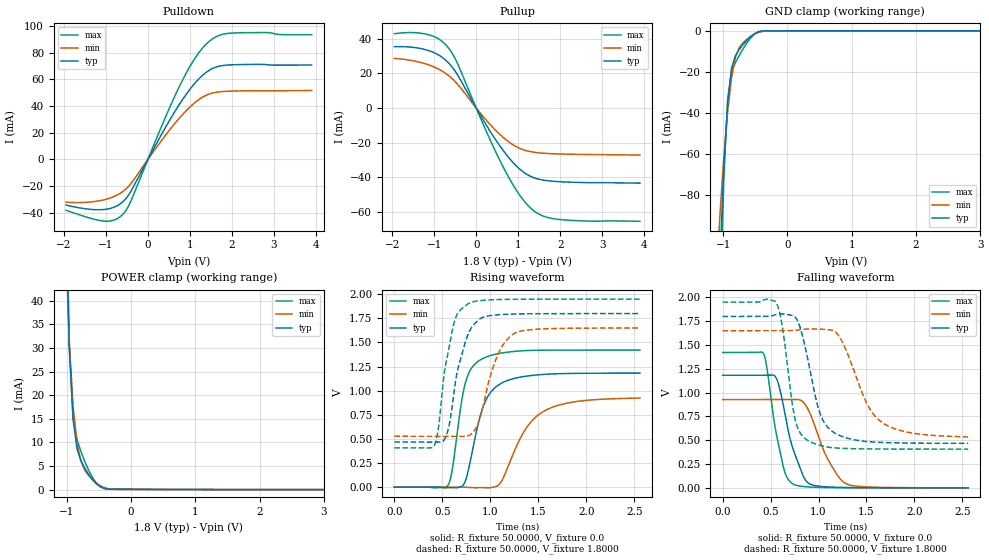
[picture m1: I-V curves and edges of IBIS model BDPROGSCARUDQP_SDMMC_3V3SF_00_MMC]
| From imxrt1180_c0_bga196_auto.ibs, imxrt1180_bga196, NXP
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[Model]  BDPROGSCARUDQP_SDMMC_3V3SF_00_MMC
|   Model BDPROGSCARUDQP_SDMMC_3V3SF_00_MMC
| This model was characterised for following simulation conditions:
| External (pad) voltage:
|   - Typ: 1.8V,   - Min: 1.65V,   - Max: 1.95V
| Library cells for typ/min/max conditions are connected as defined below:
|  IO - External Pad
|  A - Core Input
|  EN - Output Buffer Enable
|  ASRCN3V3[0] - gnde REFH3V3 gnde
|  ASRCN3V3[1] - REFH3V3 gnde gnde
|  ASRCN3V3[2] - gnde
|  ASRCN3V3[3] - gnde REFH3V3 gnde
|  ASRCP3V3[0] - vdde3v3 vdde3v3 REFL3V3
|  ASRCP3V3[1] - vdde3v3 REFL3V3 vdde3v3
|  ASRCP3V3[2] - REFL3V3 vdde3v3 vdde3v3
|  ASRCP3V3[3] - vdde3v3 REFL3V3 vdde3v3
|  IOGC - NC
|  PDRV - gnd
|  PSW - gnd
|  REFH3V3 - REFH3V3
|  REFL3V3 - REFL3V3
|  ZI - NC
|  gnd - gnd
|  gnde - gnde
|  vdd - vdd
|  vdde3v3 - vdde3v3
| All other pins connected to ground
Model_type I/O
Polarity   Non-Inverting
Enable   Active-Low
Vinl =   0.5775V
Vinh =   1.2675V
Vmeas =  0.9000V
Cref =   30.0000pF
Rref =   1.0000M
Vref =   1.8000V
C_comp   2.2202pF   2.2075pF   2.2420pF
|C_comp_pullup   1.1647pF   1.1330pF   1.1987pF
|C_comp_pulldown   0.7687pF   0.7963pF   0.7473pF
[Model Spec]
| variable   typ   min   max
Vinh   1.1700V   1.0725V   1.2675V
Vinl   0.6300V   0.5775V   0.6825V
[Temperature Range]   25.0000   0.1250k   -40.0000
[Voltage Range]   1.8000V   1.6500V   1.9500V
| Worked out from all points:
|   slope of the pulldown table from 0 to 0.27 V, typ, clamps not added: 17.2 ohm
|   slope of the pullup table from 0 to 0.27 V, typ, clamps not added: 24.6 ohm
|   GND clamp passes 1 mA (typ) near -0.49 V on its own axis
|   POWER clamp passes 1 mA (typ) near -0.52 V on its own axis
|   rising waveform, R_fixture 50.0000, V_fixture 0.0: 20-80 % time 193ps typ, 314ps min, 138ps max; typ from 0 V to 1.18 V
|   rising waveform, R_fixture 50.0000, V_fixture 1.8000: 20-80 % time 161ps typ, 200ps min, 135ps max; typ from 0.468 V to 1.8 V
|   falling waveform, R_fixture 50.0000, V_fixture 0.0: 20-80 % time 180ps typ, 236ps min, 140ps max; typ from 1.18 V to 0 V
|   falling waveform, R_fixture 50.0000, V_fixture 1.8000: 20-80 % time 186ps typ, 290ps min, 126ps max; typ from 1.8 V to 0.468 V
[Pulldown]
|Voltage   I(typ)   I(min)   I(max)
-1.95V    -34.28mA   -32.14mA   -38.27mA
-990mV    -37.37mA   -29.86mA   -46.43mA
-750mV    -35.06mA   -27.04mA   -44.73mA
-570mV    -31.01mA   -23.44mA   -40.26mA
-390mV    -23.02mA   -17.53mA   -30.03mA
390mV     22.39mA    16.91mA    29.6mA
810mV     44.08mA    33.05mA    58.46mA
1.17V     58.87mA    43.79mA    78.04mA
1.53V     67.94mA    49.57mA    90.07mA
1.77V     70.2mA     50.73mA    93.56mA
2.07V     70.86mA    51.18mA    94.66mA
3.9V      70.64mA    51.55mA    93.34mA
[Pullup]
|Voltage   I(typ)   I(min)   I(max)
-1.95V    35.27mA    28.54mA    42.76mA
-1.14V    33.09mA    24.9mA     42.2mA
-900mV    30.57mA    22.44mA    39.86mA
-660mV    25.99mA    18.7mA     34.59mA
-420mV    18.1mA     13.04mA    24.29mA
240mV     -9.816mA   -6.997mA   -13.39mA
660mV     -25.01mA   -17.28mA   -34.76mA
1.02V     -34.83mA   -23.05mA   -49.63mA
1.38V     -40.19mA   -25.49mA   -59.33mA
1.68V     -41.81mA   -26.16mA   -62.9mA
2.04V     -42.5mA    -26.5mA    -64.33mA
3.9V      -43.26mA   -27.06mA   -65.23mA
[GND_clamp]
|Voltage   I(typ)   I(min)   I(max)
-1.95V    -1.789A    -1.004A    -3.051A
-1.11V    -176.3mA   -125mA     -253.2mA
-1.05V    -112.3mA   -89.65mA   -141mA
-990mV    -66.82mA   -61.56mA   -72.04mA
-930mV    -35.58mA   -39.41mA   -33.25mA
-870mV    -18.33mA   -22.88mA   -19.96mA
-810mV    -12.12mA   -12.84mA   -15.54mA
-750mV    -9.12mA    -8.155mA   -12.04mA
-630mV    -4.535mA   -4.075mA   -5.883mA
-510mV    -1.335mA   -1.581mA   -1.518mA
-270mV    -20.22uA   -28.48uA   -26.21uA
3.9V      0A         0A         0A
[POWER_clamp]
|Voltage   I(typ)   I(min)   I(max)
-1.95V    1.733A     958.6mA    2.996A
-1.02V    63.28mA    53.98mA    74.85mA
-960mV    30.45mA    31.34mA    30.44mA
-900mV    14.89mA    17.65mA    15.05mA
-840mV    8.668mA    9.912mA    10.62mA
-780mV    6.192mA    6.041mA    8.133mA
-720mV    4.573mA    4.149mA    5.993mA
-600mV    2.107mA    2.103mA    2.589mA
-480mV    625.6uA    842.7uA    634.5uA
-360mV    113.4uA    223.3uA    106.8uA
-180mV    54.75uA    42.77uA    75.45uA
3.9V      0A         0A         0A
[Ramp]
| variable   typ   min   max
dV/dt_r  0.7089/0.1931n   0.5536/0.3137n   0.8526/0.1382n
dV/dt_f  0.7989/0.1861n   0.6687/0.2896n   0.9253/0.1263n
R_load = 50.0000
[Rising Waveform]
R_fixture= 50.0000
V_fixture= 0.0
V_fixture_min= 0.0
V_fixture_max= 0.0
|time   V(typ)   V(min)   V(max)
0s        129.7uV    120.6uV    150.1uV
558.8ps   -7.311mV   123uV      17.56mV
600.7ps   -5.725mV   190.1uV    163mV
690.8ps   3.688mV    66.72uV    822.9mV
738.3ps   57.62mV    -1.964mV   1.074V
908.6ps   783.2mV    -5.56mV    1.326V
1.102ns   1.069V     37.87mV    1.388V
1.369ns   1.15V      603.9mV    1.415V
1.577ns   1.17V      797mV      1.42V
2.56ns    1.182V     922.8mV    1.421V
[Rising Waveform]
R_fixture= 50.0000
V_fixture= 1.8000
V_fixture_min= 1.6500
V_fixture_max= 1.9500
|time   V(typ)   V(min)   V(max)
0s        467.5mV    526.6mV    407.1mV
418.4ps   467.6mV    526.7mV    435.2mV
461.2ps   466.1mV    526.7mV    620.9mV
532.5ps   512.2mV    526.7mV    1.256V
613.1ps   918.5mV    526.7mV    1.667V
778.4ps   1.609V     535.3mV    1.907V
885.2ps   1.74V      688.4mV    1.933V
1.081ns   1.787V     1.377V     1.945V
1.243ns   1.794V     1.589V     1.948V
2.56ns    1.799V     1.649V     1.949V
[Falling Waveform]
R_fixture= 50.0000
V_fixture= 0.0
V_fixture_min= 0.0
V_fixture_max= 0.0
|time   V(typ)   V(min)   V(max)
0s        1.182V     926.4mV    1.421V
426.1ps   1.181V     926.5mV    1.41V
461ps     1.181V     926.6mV    1.267V
567.9ps   1.134V     926.5mV    527.9mV
649.7ps   782.1mV    926.4mV    161.1mV
729.3ps   424.2mV    927.5mV    43.73mV
894.3ps   50.19mV    818.3mV    9.87mV
1.092ns   9.927mV    310.5mV    3.186mV
1.277ns   3.856mV    49.37mV    1.308mV
2.56ns    148.6uV    453uV      151.8uV
[Falling Waveform]
R_fixture= 50.0000
V_fixture= 1.8000
V_fixture_min= 1.6500
V_fixture_max= 1.9500
|time   V(typ)   V(min)   V(max)
0s        1.799V     1.649V     1.949V
562.2ps   1.821V     1.649V     1.938V
623.9ps   1.826V     1.649V     1.687V
759.3ps   1.79V      1.652V     706.5mV
886.1ps   1.361V     1.667V     500mV
1.019ns   773.6mV    1.665V     445mV
1.19ns    563.9mV    1.623V     418mV
1.505ns   486.1mV    882.9mV    408.9mV
1.641ns   477.6mV    702.4mV    407.8mV
2.56ns    467.7mV    534.8mV    406.9mV
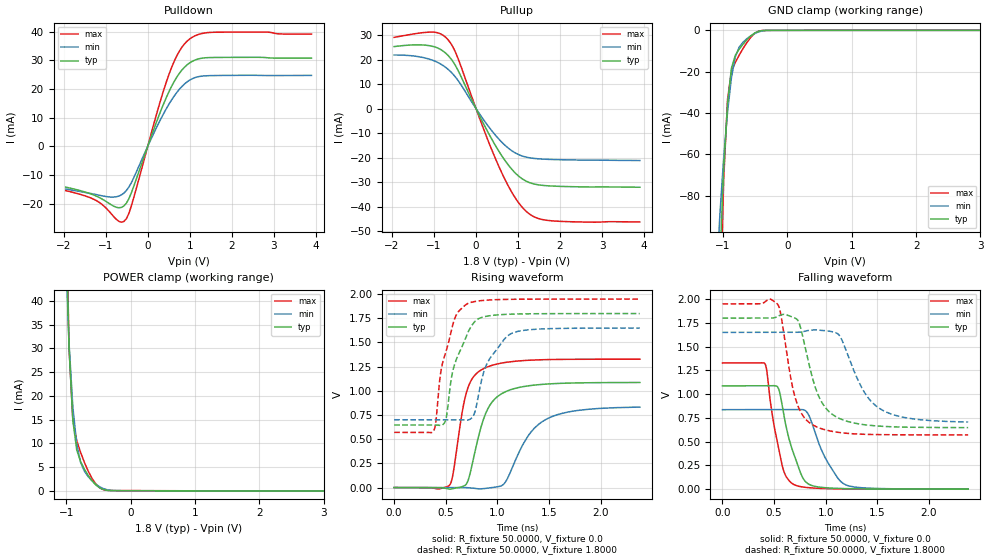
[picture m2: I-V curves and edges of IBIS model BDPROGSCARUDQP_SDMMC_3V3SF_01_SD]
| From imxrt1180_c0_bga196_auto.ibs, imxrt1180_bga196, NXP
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[Model]  BDPROGSCARUDQP_SDMMC_3V3SF_01_SD
|   Model BDPROGSCARUDQP_SDMMC_3V3SF_01_SD
| This model was characterised for following simulation conditions:
| External (pad) voltage:
|   - Typ: 1.8V,   - Min: 1.65V,   - Max: 1.95V
| Library cells for typ/min/max conditions are connected as defined below:
|  IO - External Pad
|  A - Core Input
|  EN - Output Buffer Enable
|  ASRCN3V3[0] - gnde REFH3V3 gnde
|  ASRCN3V3[1] - REFH3V3 gnde gnde
|  ASRCN3V3[2] - gnde
|  ASRCN3V3[3] - gnde REFH3V3 gnde
|  ASRCP3V3[0] - vdde3v3 vdde3v3 REFL3V3
|  ASRCP3V3[1] - vdde3v3 REFL3V3 vdde3v3
|  ASRCP3V3[2] - REFL3V3 vdde3v3 vdde3v3
|  ASRCP3V3[3] - vdde3v3 REFL3V3 vdde3v3
|  IOGC - NC
|  PDRV - vdd
|  PSW - gnd
|  REFH3V3 - REFH3V3
|  REFL3V3 - REFL3V3
|  ZI - NC
|  gnd - gnd
|  gnde - gnde
|  vdd - vdd
|  vdde3v3 - vdde3v3
| All other pins connected to ground
Model_type I/O
Polarity   Non-Inverting
Enable   Active-Low
Vinl =   0.5800V
Vinh =   1.2700V
Vmeas =  0.9000V
Cref =   30.0000pF
Rref =   1.0000M
Vref =   1.8000V
C_comp   2.2202pF   2.2075pF   2.2420pF
|C_comp_pullup   1.1648pF   1.1331pF   1.1988pF
|C_comp_pulldown   0.7687pF   0.7964pF   0.7474pF
[Model Spec]
| variable   typ   min   max
Vinh   1.1700V   1.0725V   1.2675V
Vinl   0.6300V   0.5775V   0.6825V
[Temperature Range]   25.0000   0.1250k   -40.0000
[Voltage Range]   1.8000V   1.6500V   1.9500V
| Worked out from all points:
|   slope of the pulldown table from 0 to 0.27 V, typ, clamps not added: 24.9 ohm
|   slope of the pullup table from 0 to 0.27 V, typ, clamps not added: 29.4 ohm
|   GND clamp passes 1 mA (typ) near -0.49 V on its own axis
|   POWER clamp passes 1 mA (typ) near -0.52 V on its own axis
|   rising waveform, R_fixture 50.0000, V_fixture 0.0: 20-80 % time 187ps typ, 285ps min, 137ps max; typ from 0 V to 1.09 V
|   rising waveform, R_fixture 50.0000, V_fixture 1.8000: 20-80 % time 176ps typ, 210ps min, 147ps max; typ from 0.647 V to 1.8 V
|   falling waveform, R_fixture 50.0000, V_fixture 0.0: 20-80 % time 160ps typ, 212ps min, 127ps max; typ from 1.09 V to 0 V
|   falling waveform, R_fixture 50.0000, V_fixture 1.8000: 20-80 % time 199ps typ, 270ps min, 152ps max; typ from 1.8 V to 0.648 V
[Pulldown]
|Voltage   I(typ)   I(min)   I(max)
-1.95V    -14.21mA   -14.86mA   -15.41mA
-1.23V    -17.29mA   -16.8mA    -18.84mA
-870mV    -20.35mA   -17.67mA   -23.46mA
-630mV    -21.29mA   -16.94mA   -26.43mA
-510mV    -19.83mA   -15.42mA   -25.27mA
-390mV    -16.22mA   -12.69mA   -20.79mA
210mV     8.519mA    6.569mA    11.21mA
510mV     19.18mA    14.81mA    25.24mA
750mV     25.39mA    19.84mA    33.11mA
1.05V     29.56mA    23.52mA    37.96mA
1.53V     30.98mA    24.68mA    39.77mA
3.9V      30.78mA    24.74mA    39.15mA
[Pullup]
|Voltage   I(typ)   I(min)   I(max)
-1.95V    25.33mA    21.9mA     29.09mA
-1.02V    25.38mA    19.66mA    31.26mA
-840mV    24.12mA    18.19mA    30.5mA
-660mV    21.62mA    15.97mA    28.01mA
-420mV    15.32mA    11.29mA    20.13mA
180mV     -6.218mA   -4.554mA   -8.313mA
600mV     -18.93mA   -13.47mA   -25.75mA
960mV     -26.73mA   -18.33mA   -37.13mA
1.26V     -30.13mA   -20.04mA   -42.9mA
1.5V      -31.16mA   -20.52mA   -44.96mA
1.86V     -31.66mA   -20.8mA    -45.9mA
3.9V      -32.11mA   -21.2mA    -46.28mA
[GND_clamp]
|Voltage   I(typ)   I(min)   I(max)
-1.95V    -1.789A    -1.004A    -3.051A
-1.11V    -176.3mA   -125mA     -253.2mA
-1.05V    -112.3mA   -89.65mA   -141mA
-990mV    -66.82mA   -61.56mA   -72.04mA
-930mV    -35.58mA   -39.41mA   -33.25mA
-870mV    -18.33mA   -22.88mA   -19.96mA
-810mV    -12.12mA   -12.84mA   -15.54mA
-750mV    -9.12mA    -8.155mA   -12.04mA
-630mV    -4.535mA   -4.075mA   -5.883mA
-510mV    -1.335mA   -1.581mA   -1.518mA
-270mV    -20.22uA   -28.48uA   -26.21uA
3.9V      0A         0A         0A
[POWER_clamp]
|Voltage   I(typ)   I(min)   I(max)
-1.95V    1.733A     958.6mA    2.996A
-1.02V    63.28mA    53.98mA    74.85mA
-960mV    30.45mA    31.34mA    30.44mA
-900mV    14.89mA    17.65mA    15.05mA
-840mV    8.668mA    9.912mA    10.62mA
-780mV    6.192mA    6.041mA    8.133mA
-720mV    4.573mA    4.149mA    5.993mA
-600mV    2.107mA    2.103mA    2.589mA
-480mV    625.6uA    842.7uA    634.5uA
-360mV    113.4uA    223.3uA    106.8uA
-180mV    54.75uA    42.77uA    75.45uA
3.9V      0A         0A         0A
[Ramp]
| variable   typ   min   max
dV/dt_r  0.6518/0.1871n   0.4990/0.2850n   0.7963/0.1365n
dV/dt_f  0.6910/0.1987n   0.5656/0.2704n   0.8269/0.1524n
R_load = 50.0000
[Rising Waveform]
R_fixture= 50.0000
V_fixture= 0.0
V_fixture_min= 0.0
V_fixture_max= 0.0
|time   V(typ)   V(min)   V(max)
0s        166.1uV    149.5uV    196.4uV
541.3ps   -16.36mV   120.1uV    31.26mV
571.6ps   -10.36mV   160uV      146.2mV
695.9ps   31.84mV    -143.4uV   967.3mV
759.8ps   257.4mV    -5.331mV   1.132V
863.6ps   700.8mV    -11.37mV   1.228V
1.067ns   984.9mV    41.5mV     1.292V
1.277ns   1.048V     499.6mV    1.315V
1.463ns   1.07V      700.6mV    1.323V
2.38ns    1.087V     831.8mV    1.327V
[Rising Waveform]
R_fixture= 50.0000
V_fixture= 1.8000
V_fixture_min= 1.6500
V_fixture_max= 1.9500
|time   V(typ)   V(min)   V(max)
0s        647.2mV    701.4mV    570.8mV
384.7ps   647.7mV    701.5mV    591.7mV
472.3ps   650mV      701.5mV    1.301V
505ps     723mV      701.6mV    1.417V
577.1ps   1.243V     701.9mV    1.716V
711.1ps   1.596V     698mV      1.902V
778.7ps   1.714V     770.3mV    1.923V
905.9ps   1.774V     1.295V     1.939V
1.133ns   1.793V     1.592V     1.946V
2.38ns    1.799V     1.649V     1.949V
[Falling Waveform]
R_fixture= 50.0000
V_fixture= 0.0
V_fixture_min= 0.0
V_fixture_max= 0.0
|time   V(typ)   V(min)   V(max)
0s        1.087V     836.2mV    1.327V
412.2ps   1.086V     836.3mV    1.318V
483ps     1.089V     836.4mV    777.5mV
533.7ps   1.076V     836.4mV    486.1mV
580.2ps   867.9mV    836.2mV    241.6mV
693.8ps   362.1mV    836.4mV    47.37mV
820.5ps   63.11mV    806.5mV    17.13mV
997ps     15.41mV    326.4mV    6.433mV
1.188ns   5.949mV    48.68mV    2.559mV
2.38ns    194.4uV    468.8uV    201.5uV
[Falling Waveform]
R_fixture= 50.0000
V_fixture= 1.8000
V_fixture_min= 1.6500
V_fixture_max= 1.9500
|time   V(typ)   V(min)   V(max)
0s        1.799V     1.649V     1.949V
536ps     1.819V     1.649V     1.942V
704.4ps   1.799V     1.649V     961.9mV
752.8ps   1.714V     1.652V     822mV
883.9ps   1.124V     1.675V     670.4mV
988.2ps   870.4mV    1.668V     626.3mV
1.13ns    745mV      1.621V     596.4mV
1.377ns   677.4mV    1.015V     577.1mV
1.552ns   660.9mV    829.4mV    573.3mV
2.38ns    647.5mV    706.5mV    570.8mV
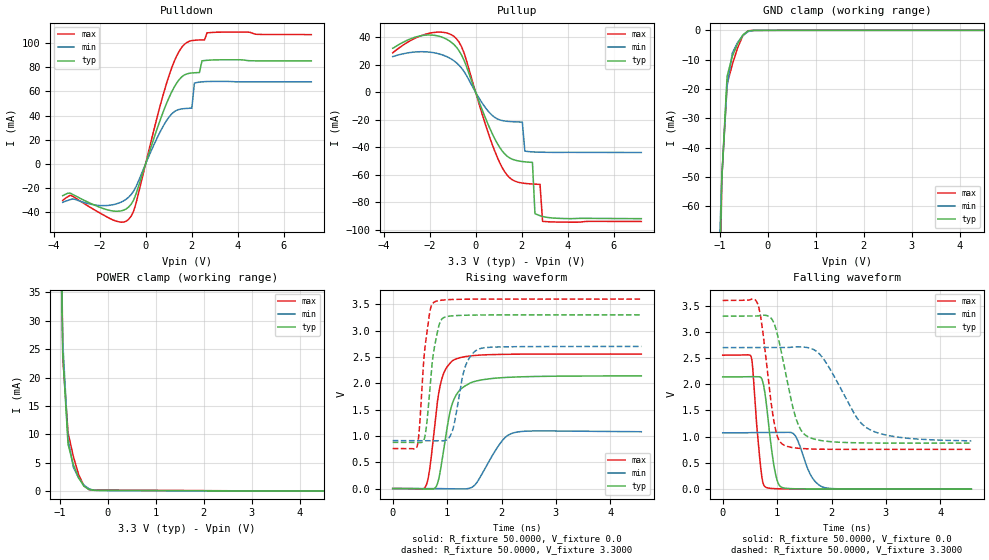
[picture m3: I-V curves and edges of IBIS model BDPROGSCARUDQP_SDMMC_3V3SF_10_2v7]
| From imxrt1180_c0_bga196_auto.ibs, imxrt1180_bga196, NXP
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[Model]  BDPROGSCARUDQP_SDMMC_3V3SF_10_2v7
|   Model BDPROGSCARUDQP_SDMMC_3V3SF_10_2v7
| This model was characterised for following simulation conditions:
| External (pad) voltage:
|   - Typ: 3.3V,   - Min: 2.7V,   - Max: 3.6V
| Library cells for typ/min/max conditions are connected as defined below:
|  IO - External Pad
|  A - Core Input
|  EN - Output Buffer Enable
|  ASRCN3V3[0] - REFH3V3
|  ASRCN3V3[1] - REFH3V3 REFH3V3 gnde
|  ASRCN3V3[2] - gnde REFH3V3 gnde
|  ASRCN3V3[3] - gnde REFH3V3 gnde
|  ASRCP3V3[0] - vdde3v3 REFL3V3 REFL3V3
|  ASRCP3V3[1] - vdde3v3 REFL3V3 vdde3v3
|  ASRCP3V3[2] - REFL3V3 REFL3V3 vdde3v3
|  ASRCP3V3[3] - REFL3V3 REFL3V3 vdde3v3
|  IOGC - NC
|  PDRV - gnd
|  PSW - vdd
|  REFH3V3 - REFH3V3
|  REFL3V3 - REFL3V3
|  ZI - NC
|  gnd - gnd
|  gnde - gnde
|  vdd - vdd
|  vdde3v3 - vdde3v3
| All other pins connected to ground
Model_type I/O
Polarity   Non-Inverting
Enable   Active-Low
Vinl =   0.6750V
Vinh =   2.2500V
Vmeas =  1.6500V
Cref =   30.0000pF
Rref =   1.0000M
Vref =   3.3000V
C_comp   2.1236pF   2.1018pF   2.1437pF
|C_comp_pullup   0.3619pF   0.3778pF   0.3515pF
|C_comp_pulldown   0.6265pF   0.6611pF   0.5987pF
[Model Spec]
| variable   typ   min   max
Vinh   2.0625V   1.6875V   2.2500V
Vinl   0.8250V   0.6750V   0.9000V
[Temperature Range]   25.0000   0.1250k   -40.0000
[Voltage Range]   3.3000V   2.7000V   3.6000V
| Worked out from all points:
|   slope of the pulldown table from 0 to 0.495 V, typ, clamps not added: 17.2 ohm
|   slope of the pullup table from 0 to 0.495 V, typ, clamps not added: 23 ohm
|   GND clamp passes 1 mA (typ) near -0.48 V on its own axis
|   POWER clamp passes 1 mA (typ) near -0.51 V on its own axis
|   rising waveform, R_fixture 50.0000, V_fixture 0.0: 20-80 % time 243ps typ, 372ps min, 195ps max; typ from 0 V to 2.14 V
|   rising waveform, R_fixture 50.0000, V_fixture 3.3000: 20-80 % time 152ps typ, 204ps min, 136ps max; typ from 0.878 V to 3.3 V
|   falling waveform, R_fixture 50.0000, V_fixture 0.0: 20-80 % time 153ps typ, 242ps min, 118ps max; typ from 2.14 V to 0 V
|   falling waveform, R_fixture 50.0000, V_fixture 3.3000: 20-80 % time 307ps typ, 589ps min, 203ps max; typ from 3.3 V to 0.877 V
[Pulldown]
|Voltage   I(typ)   I(min)   I(max)
-3.6V     -26.23mA   -31.7mA    -30.08mA
-3.27V    -24.11mA   -29.48mA   -25.84mA
-1.4V     -38.9mA    -33.61mA   -46.39mA
-630mV    -33.34mA   -25.36mA   -43.24mA
1.02V     54.81mA    38.78mA    73.04mA
1.79V     74.36mA    45.87mA    100.3mA
2.01V     75.15mA    46.1mA     101.9mA
2.12V     75.31mA    66.8mA     102.1mA
2.23V     75.41mA    67.25mA    102.3mA
2.56V     85.39mA    67.96mA    102.4mA
2.89V     85.84mA    68.14mA    108.6mA
7.2V      85.14mA    67.86mA    106.8mA
[Pullup]
|Voltage   I(typ)   I(min)   I(max)
-3.6V     31.94mA    25.87mA    28.66mA
-2.04V    41.59mA    29.2mA     42.73mA
-830mV    32.67mA    21.37mA    38.87mA
490mV     -21.3mA    -12.66mA   -26.71mA
1.15V     -42.62mA   -20.6mA    -54.63mA
2.03V     -50.44mA   -21.75mA   -66.08mA
2.14V     -50.64mA   -42.84mA   -66.33mA
2.47V     -51.06mA   -43.43mA   -66.78mA
2.58V     -88.31mA   -43.52mA   -66.88mA
2.8V      -89.83mA   -43.64mA   -67.05mA
2.91V     -90.37mA   -43.68mA   -93.93mA
7.2V      -91.99mA   -43.87mA   -94.02mA
[GND_clamp]
|Voltage   I(typ)   I(min)   I(max)
-3.6V     -5.131A    -2.873A    -8.762A
-1.07V    -134.2mA   -102.1mA   -176.8mA
-960mV    -50.84mA   -50.69mA   -50.43mA
-850mV    -15.74mA   -19.08mA   -18.44mA
-740mV    -8.808mA   -7.744mA   -11.63mA
-630mV    -4.596mA   -4.116mA   -5.959mA
-520mV    -1.551mA   -1.763mA   -1.8mA
-410mV    -182.3uA   -415.1uA   -135.3uA
-190mV    -16.94uA   -13.14uA   -23.35uA
7.2V      0A         0A         0A
[POWER_clamp]
|Voltage   I(typ)   I(min)   I(max)
-3.6V     5.01A      2.758A     8.682A
-1.05V    90.64mA    70.14mA    118.9mA
-940mV    24.29mA    26.26mA    23.58mA
-830mV    8.246mA    9.16mA     10.3mA
-720mV    4.663mA    4.194mA    6.11mA
-610mV    2.344mA    2.275mA    2.91mA
-500mV    850.8uA    1.038mA    919.3uA
-390mV    222uA      354.3uA    219.3uA
-280mV    111uA      109.1uA    149.6uA
-60mV     99.3uA     64.48uA    139.3uA
7.2V      0A         0A         0A
[Ramp]
| variable   typ   min   max
dV/dt_r  1.2834/0.2433n   0.6474/0.3721n   1.5326/0.1947n
dV/dt_f  1.4527/0.3068n   1.0670/0.5891n   1.7034/0.2029n
R_load = 50.0000
[Rising Waveform]
R_fixture= 50.0000
V_fixture= 0.0
V_fixture_min= 0.0
V_fixture_max= 0.0
|time   V(typ)   V(min)   V(max)
0s        133.3uV    103.6uV    154.7uV
606.6ps   -10.76mV   145.8uV    42.15mV
677.4ps   -9.418mV   152.3uV    351.3mV
788.8ps   20.78mV    -18.95uV   1.357V
876.4ps   342.6mV    -1.375mV   1.974V
1.038ns   1.377V     -5.963mV   2.361V
1.126ns   1.694V     -6.173mV   2.444V
1.499ns   2.032V     56.75mV    2.526V
2.21ns    2.116V     1.054V     2.551V
4.57ns    2.139V     1.079V     2.554V
[Rising Waveform]
R_fixture= 50.0000
V_fixture= 3.3000
V_fixture_min= 2.7000
V_fixture_max= 3.6000
|time   V(typ)   V(min)   V(max)
0s        877.7mV    909.9mV    759.5mV
452.6ps   877.1mV    910mV      814.5mV
599.5ps   1.03V      910mV      2.736V
688.2ps   1.969V     910.1mV    3.388V
761.3ps   2.651V     910mV      3.54V
884.5ps   3.191V     906.2mV    3.575V
1.069ns   3.277V     1.024V     3.59V
1.329ns   3.291V     2.304V     3.595V
1.575ns   3.296V     2.646V     3.597V
4.57ns    3.299V     2.699V     3.598V
[Falling Waveform]
R_fixture= 50.0000
V_fixture= 0.0
V_fixture_min= 0.0
V_fixture_max= 0.0
|time   V(typ)   V(min)   V(max)
0s        2.139V     1.074V     2.554V
523.8ps   2.144V     1.078V     2.522V
697.8ps   2.133V     1.081V     416.8mV
793.6ps   1.701V     1.081V     35.34mV
949.4ps   402.6mV    1.081V     10.37mV
1.084ns   36.21mV    1.082V     5.869mV
1.328ns   7.264mV    1.027V     2.478mV
1.626ns   3.1mV      252.8mV    962.3uV
1.857ns   1.716mV    34.01mV    519.8uV
4.57ns    133.5uV    185.9uV    154.6uV
[Falling Waveform]
R_fixture= 50.0000
V_fixture= 3.3000
V_fixture_min= 2.7000
V_fixture_max= 3.6000
|time   V(typ)   V(min)   V(max)
0s        3.299V     2.699V     3.598V
641.4ps   3.302V     2.699V     3.537V
721ps     3.317V     2.699V     3.127V
950.5ps   3.143V     2.7V       1.244V
1.113ns   2.437V     2.7V       847.7mV
1.351ns   1.336V     2.713V     783.8mV
1.585ns   989.6mV    2.693V     767.5mV
1.851ns   920.4mV    2.486V     761mV
2.672ns   880.4mV    1.154V     758.2mV
4.57ns    877.3mV    920.5mV    759.2mV
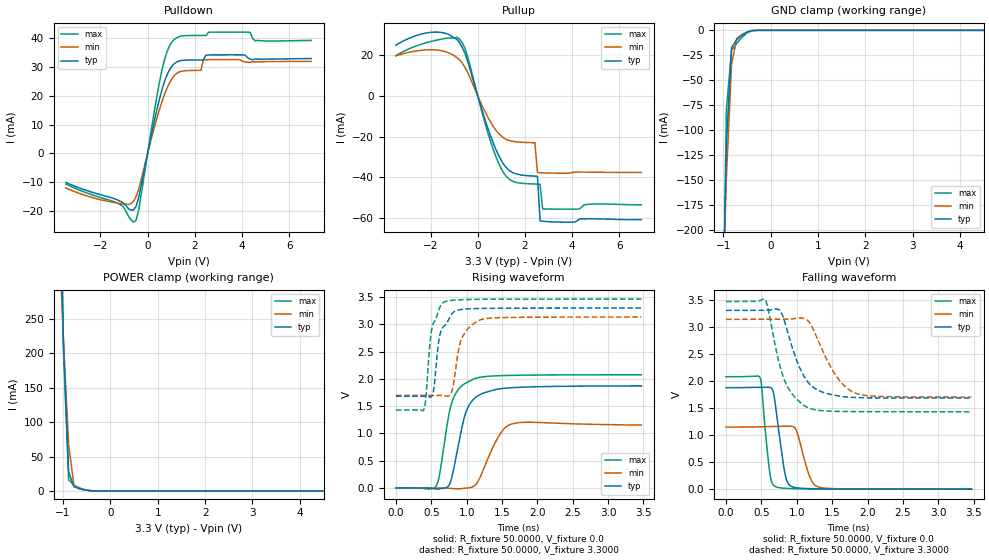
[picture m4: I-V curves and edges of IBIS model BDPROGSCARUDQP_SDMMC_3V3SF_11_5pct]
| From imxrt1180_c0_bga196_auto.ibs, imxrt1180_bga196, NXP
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[Model]  BDPROGSCARUDQP_SDMMC_3V3SF_11_5pct
|   Model BDPROGSCARUDQP_SDMMC_3V3SF_11_5pct
| This model was characterised for following simulation conditions:
| External (pad) voltage:
|   - Typ: 3.3V,   - Min: 3.135V,   - Max: 3.465V
| Library cells for typ/min/max conditions are connected as defined below:
|  IO - External Pad
|  A - Core Input
|  EN - Output Buffer Enable
|  ASRCN3V3[0] - REFH3V3
|  ASRCN3V3[1] - REFH3V3 REFH3V3 gnde
|  ASRCN3V3[2] - gnde
|  ASRCN3V3[3] - gnde REFH3V3 gnde
|  ASRCP3V3[0] - vdde3v3 REFL3V3 REFL3V3
|  ASRCP3V3[1] - vdde3v3 REFL3V3 vdde3v3
|  ASRCP3V3[2] - REFL3V3 vdde3v3 vdde3v3
|  ASRCP3V3[3] - REFL3V3 REFL3V3 vdde3v3
|  IOGC - NC
|  PDN - vdd
|  PDRV - vdd
|  PSW - vdd
|  PUN - vdd
|  REFH3V3 - REFH3V3
|  REFL3V3 - REFL3V3
|  ZI - NC
|  gnd - gnd
|  gnde - gnde
|  vdd - vdd
|  vdde3v3 - vdde3v3
| All other pins connected to ground
Model_type I/O
Polarity   Non-Inverting
Enable   Active-Low
Vinl =   0.7500V
Vinh =   2.2500V
Vmeas =  1.6500V
Cref =   30.0000pF
Rref =   1.0000M
Vref =   3.3000V
C_comp   2.0930pF   2.0588pF   2.1394pF
|C_comp_pullup   0.3785pF   0.3918pF   0.3681pF
|C_comp_pulldown   0.6262pF   0.6586pF   0.5998pF
[Model Spec]
| variable   typ   min   max
Vinh   2.0625V   1.9594V   2.1656V
Vinl   0.8250V   0.7837V   0.8662V
[Temperature Range]   25.0000   0.1250k   -40.0000
[Voltage Range]   3.3000V   3.1350V   3.4650V
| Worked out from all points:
|   slope of the pulldown table from 0 to 0.495 V, typ, clamps not added: 26.6 ohm
|   slope of the pullup table from 0 to 0.495 V, typ, clamps not added: 27.4 ohm
|   GND clamp passes 1 mA (typ) near -0.44 V on its own axis
|   POWER clamp passes 1 mA (typ) near -0.50 V on its own axis
|   rising waveform, R_fixture 50.0000, V_fixture 0.0: 20-80 % time 205ps typ, 240ps min, 179ps max; typ from 0 V to 1.87 V
|   rising waveform, R_fixture 50.0000, V_fixture 3.3000: 20-80 % time 135ps typ, 154ps min, 110ps max; typ from 1.68 V to 3.3 V
|   falling waveform, R_fixture 50.0000, V_fixture 0.0: 20-80 % time 117ps typ, 149ps min, 88.8ps max; typ from 1.87 V to 0 V
|   falling waveform, R_fixture 50.0000, V_fixture 3.3000: 20-80 % time 287ps typ, 349ps min, 257ps max; typ from 3.3 V to 1.68 V
[Pulldown]
|Voltage   I(typ)   I(min)   I(max)
-3.465V   -10.11mA   -12.03mA   -10.64mA
-1.265V   -16.2mA    -17.29mA   -17.3mA
-495mV    -18.52mA   -15.14mA   -23.3mA
-385mV    -15.6mA    -12.63mA   -19.99mA
605mV     22.01mA    17.88mA    28.83mA
935mV     29.11mA    24.61mA    37.41mA
1.265V    31.87mA    27.95mA    40.27mA
2.255V    32.42mA    28.83mA    40.91mA
2.365V    32.42mA    32.44mA    40.91mA
4.235V    33.22mA    31.65mA    42.08mA
4.565V    32.74mA    31.8mA     39.06mA
6.93V     32.91mA    31.93mA    39.2mA
[Pullup]
|Voltage   I(typ)   I(min)   I(max)
-3.465V   25.08mA    19.77mA    19.93mA
-1.87V    31.46mA    22.73mA    27.17mA
-770mV    26.31mA    17.83mA    28.01mA
-440mV    17.63mA    11.93mA    19.96mA
440mV     -16.26mA   -10.73mA   -18.55mA
990mV     -31.64mA   -19.72mA   -35.71mA
1.43V     -37.49mA   -22.25mA   -41.78mA
2.42V     -39.53mA   -23.08mA   -43.41mA
2.53V     -39.59mA   -37.72mA   -43.45mA
2.64V     -61.57mA   -37.82mA   -43.49mA
2.75V     -61.74mA   -37.89mA   -55.68mA
6.93V     -60.97mA   -37.66mA   -53.64mA
[GND_clamp]
|Voltage   I(typ)   I(min)   I(max)
-3.465V   -6.61A     -3.625A    -11.02A
-1.045V   -379.3mA   -320.9mA   -439.5mA
-935mV    -115.6mA   -149.2mA   -80.36mA
-825mV    -17.39mA   -34.03mA   -20.04mA
-715mV    -9.283mA   -8.196mA   -13.09mA
-605mV    -4.963mA   -4.061mA   -7.102mA
-495mV    -1.742mA   -1.709mA   -2.392mA
-385mV    -190.8uA   -374.3uA   -174uA
-275mV    -4.391uA   -28.37uA   -1.38uA
6.93V     0A         0A         0A
[POWER_clamp]
|Voltage   I(typ)   I(min)   I(max)
-3.465V   6.781A     3.709A     11.35A
-1.1V     518.6mA    402.6mA    656.4mA
-990mV    215.3mA    216.5mA    203.9mA
-880mV    27.02mA    66.67mA    15.93mA
-770mV    6.184mA    8.45mA     8.32mA
-660mV    3.401mA    3.057mA    4.697mA
-550mV    1.523mA    1.506mA    2.035mA
-330mV    50.46uA    136.8uA    38uA
6.93V     0A         0A         0A
[Ramp]
| variable   typ   min   max
dV/dt_r  1.1232/0.2054n   0.6917/0.2398n   1.2452/0.1789n
dV/dt_f  0.9710/0.2867n   0.8611/0.3494n   1.2216/0.2574n
R_load = 50.0000
[Rising Waveform]
R_fixture= 50.0000
V_fixture= 0.0
V_fixture_min= 0.0
V_fixture_max= 0.0
|time   V(typ)   V(min)   V(max)
0s        34.73nV    999.1nV    53.54nV
566.7ps   -19.77mV   6.685uV    32.28mV
619ps     -16.61mV   -467.2uV   258mV
741.3ps   32.17mV    -4.745mV   1.294V
825.4ps   405.4mV    -13.52mV   1.683V
971.6ps   1.314V     -6.65mV    1.912V
1.095ns   1.623V     25.99mV    1.995V
1.454ns   1.816V     947.4mV    2.059V
1.627ns   1.838V     1.168V     2.065V
3.47ns    1.872V     1.153V     2.075V
[Rising Waveform]
R_fixture= 50.0000
V_fixture= 3.3000
V_fixture_min= 3.1350
V_fixture_max= 3.4650
|time   V(typ)   V(min)   V(max)
0s        1.681V     1.699V     1.429V
394.9ps   1.684V     1.699V     1.438V
421.9ps   1.684V     1.699V     1.627V
505.8ps   1.68V      1.699V     2.907V
612.3ps   2.748V     1.7V       3.288V
684.3ps   2.973V     1.691V     3.41V
794.9ps   3.199V     1.794V     3.443V
932.4ps   3.276V     2.748V     3.454V
1.179ns   3.293V     3.076V     3.46V
3.47ns    3.3V       3.135V     3.465V
[Falling Waveform]
R_fixture= 50.0000
V_fixture= 0.0
V_fixture_min= 0.0
V_fixture_max= 0.0
|time   V(typ)   V(min)   V(max)
0s        1.873V     1.145V     2.075V
481.7ps   1.881V     1.151V     2.058V
617.7ps   1.879V     1.153V     305.2mV
701.7ps   1.516V     1.156V     44.05mV
834.5ps   277.5mV    1.161V     15.91mV
936.2ps   43.63mV    1.159V     10.02mV
1.008ns   22.44mV    1.038V     7.707mV
1.195ns   9.096mV    191.7mV    4.208mV
1.298ns   6.632mV    43.88mV    3.1mV
3.47ns    119.1uV    252.3uV    61.67uV
[Falling Waveform]
R_fixture= 50.0000
V_fixture= 3.3000
V_fixture_min= 3.1350
V_fixture_max= 3.4650
|time   V(typ)   V(min)   V(max)
0s        3.3V       3.135V     3.465V
551.4ps   3.302V     3.135V     3.497V
595.8ps   3.304V     3.135V     3.325V
739.1ps   3.318V     3.137V     2.392V
826.2ps   3.104V     3.136V     2.01V
991ps     2.402V     3.156V     1.673V
1.154ns   1.983V     3.115V     1.506V
1.526ns   1.737V     2.153V     1.437V
1.792ns   1.694V     1.795V     1.432V
3.47ns    1.682V     1.7V       1.429V
